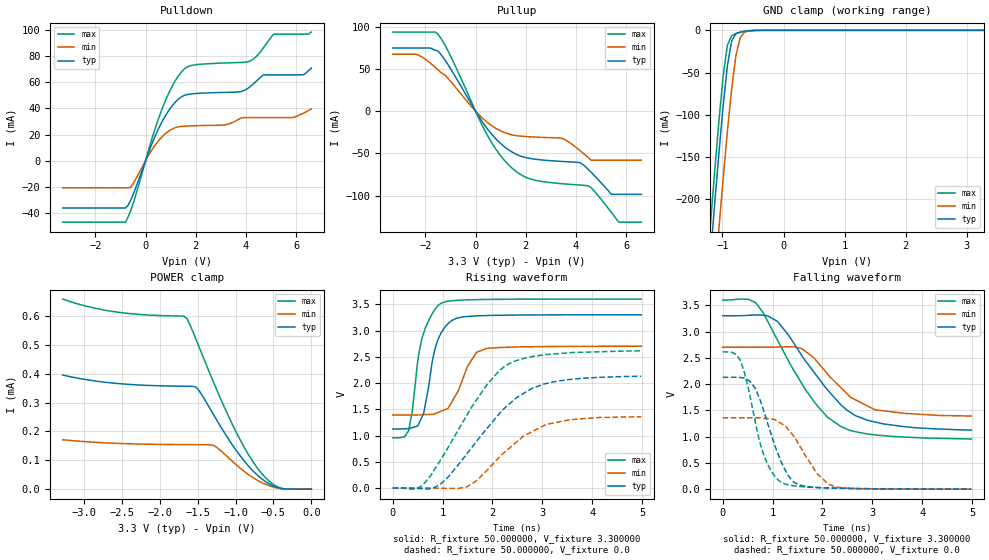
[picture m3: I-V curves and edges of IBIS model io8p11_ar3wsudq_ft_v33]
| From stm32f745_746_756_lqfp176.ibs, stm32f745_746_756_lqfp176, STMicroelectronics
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|   Model io8p11_ar3wsudq_ft_v33
[Model]  io8p11_ar3wsudq_ft_v33
Model_type I/O
Polarity   Non-Inverting
Enable   Active-Low
Vinl =   0.990000V
Vinh =   2.310000V
Vmeas =  1.650000V
Cref =   30.000000pF
Rref =   100.000000M
Vref =   0.0V
C_comp   3.857500pF   3.760500pF   3.941700pF
[Temperature Range]   25.000000   0.125000k   -40.000000
[Pullup Reference]   3.300000V   2.700000V   3.600000V
[Pulldown Reference]   0.0V   0.0V   0.0V
[POWER Clamp Reference]   3.300000V   2.700000V   3.600000V
[GND Clamp Reference]   0.0V   0.0V   0.0V
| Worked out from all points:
|   slope of the pulldown table from 0 to 0.495 V, typ, clamps not added: 20.9 ohm
|   slope of the pullup table from 0 to 0.495 V, typ, clamps not added: 22.6 ohm
|   GND clamp passes 1 mA (typ) near -0.62 V on its own axis
|   rising waveform, R_fixture 50.000000, V_fixture 3.300000: 20-80 % time 277ps typ, 389ps min, 271ps max; typ from 1.12 V to 3.3 V
|   rising waveform, R_fixture 50.000000, V_fixture 0.0: 20-80 % time 1.16ns typ, 999ps min, 1.05ns max; typ from 0 V to 2.13 V
|   falling waveform, R_fixture 50.000000, V_fixture 3.300000: 20-80 % time 1.06ns typ, 876ps min, 1.03ns max; typ from 3.3 V to 1.12 V
|   falling waveform, R_fixture 50.000000, V_fixture 0.0: 20-80 % time 473ps typ, 561ps min, 410ps max; typ from 2.13 V to 0 V
[Pulldown]
|Voltage   I(typ)   I(min)   I(max)
-3.3V     -36.18mA   -20.77mA   -47.07mA
-800mV    -36.18mA   -20.77mA   -47.07mA
-600mV    -30.5mA    -20.52mA   -38.69mA
700mV     31.4mA     19.11mA    41.71mA
1.2V      45.15mA    25.37mA    61.75mA
1.6V      50.35mA    26.5mA     71.06mA
3.1V      52.28mA    27.26mA    74.76mA
4.1V      55.7mA     32.99mA    75.8mA
4.7V      65.72mA    32.99mA    86.64mA
5.1V      65.72mA    32.99mA    96.89mA
6.3V      65.85mA    36.5mA     96.89mA
6.6V      70.91mA    39.71mA    98.45mA
[Pullup]
|Voltage   I(typ)   I(min)   I(max)
-3.3V     74.74mA    67.41mA    93.6mA
-2.3V     74.74mA    66.57mA    93.6mA
-1.5V     71.35mA    49.01mA    91.01mA
-1V       50.51mA    35.5mA     65.49mA
500mV     -22.07mA   -14mA      -30.03mA
1.6V      -50.64mA   -28.81mA   -70.96mA
3.5V      -59.53mA   -32.72mA   -85.92mA
4.2V      -61.52mA   -47.6mA    -87.46mA
4.5V      -69.21mA   -55.15mA   -88.43mA
5.4V      -98.3mA    -57.9mA    -119.4mA
5.7V      -98.3mA    -57.9mA    -131.3mA
6.6V      -98.3mA    -57.9mA    -131.3mA
[GND_clamp]
|Voltage   I(typ)   I(min)   I(max)
-3.3V     -2.332A    -2.407A    -2.312A
-1.2V     -270.2mA   -361.4mA   -232.1mA
-1.13V    -207.3mA   -298.1mA   -169mA
-1.06V    -146.7mA   -236.2mA   -108.8mA
-990mV    -90.18mA   -176.4mA   -54.96mA
-920mV    -42.21mA   -120mA     -17.68mA
-850mV    -12.57mA   -69.47mA   -6.265mA
-780mV    -3.971mA   -30.01mA   -3.886mA
-710mV    -2.1mA     -8.615mA   -2.382mA
-640mV    -1.148mA   -2.283mA   -1.22mA
-570mV    -524uA     -821.5uA   -476.8uA
3.28V     0A         0A         0A
[POWER_clamp]
|Voltage   I(typ)   I(min)   I(max)
-3.28V    395.3uA    171.3uA    658.7uA
-2.6V     367.1uA    159uA      614.9uA
-1.68V    356.7uA    154.4uA    599.4uA
-1.64V    356.5uA    154.4uA    590.8uA
-1.52V    353.6uA    154.3uA    518.3uA
-1.48V    341.1uA    154.2uA    492.3uA
-1.28V    253.6uA    150.4uA    364.2uA
-960mV    123.1uA    77.55uA    181.6uA
-720mV    50.52uA    32.03uA    76.18uA
-560mV    18.94uA    12.27uA    28.65uA
-440mV    5.104uA    3.69uA     7.327uA
0V        0A         0A         0A
[Ramp]
| variable   typ   min   max
dV/dt_r  1.26480/1.15826n   0.80718/0.99319n   1.56168/1.04884n
dV/dt_f  1.28058/1.04420n   0.77238/0.86423n   1.57183/1.02291n
R_load = 50.000000
[Rising Waveform]
R_fixture= 50.000000
V_fixture= 3.300000
V_fixture_min= 2.700000
V_fixture_max= 3.600000
|time   V(typ)   V(min)   V(max)
0s        1.124V     1.392V     954.2mV
320.3ps   1.132V     1.392V     1.095V
510.5ps   1.198V     1.392V     2.472V
650.7ps   1.572V     1.398V     3.038V
830.8ps   2.587V     1.409V     3.379V
971ps     2.956V     1.464V     3.518V
1.111ns   3.131V     1.521V     3.558V
1.682ns   3.279V     2.586V     3.588V
1.882ns   3.285V     2.658V     3.592V
4.985ns   3.3V       2.7V       3.599V
[Rising Waveform]
R_fixture= 50.000000
V_fixture= 0.0
V_fixture_min= 0.0
V_fixture_max= 0.0
|time   V(typ)   V(min)   V(max)
0s        211.3uV    82.5uV     620.3uV
550.6ps   -10.61mV   -118.1uV   23.34mV
951ps     68.5mV     -3.812mV   522.2mV
1.491ns   657mV      24.76mV    1.394V
1.882ns   1.125V     327.8mV    1.959V
2.282ns   1.554V     713.3mV    2.341V
2.783ns   1.893V     1.068V     2.502V
3.073ns   1.99V      1.209V     2.542V
3.574ns   2.07V      1.304V     2.578V
4.985ns   2.129V     1.359V     2.612V
[Falling Waveform]
R_fixture= 50.000000
V_fixture= 3.300000
V_fixture_min= 2.700000
V_fixture_max= 3.600000
|time   V(typ)   V(min)   V(max)
0s        3.3V       2.7V       3.599V
660.7ps   3.315V     2.7V       3.55V
810.8ps   3.309V     2.701V     3.362V
1.101ns   3.19V      2.705V     2.832V
1.582ns   2.549V     2.679V     2.015V
2.102ns   1.889V     2.19V      1.369V
2.362ns   1.611V     1.937V     1.198V
2.663ns   1.399V     1.7V       1.094V
3.063ns   1.277V     1.509V     1.032V
4.985ns   1.124V     1.392V     954.2mV
[Falling Waveform]
R_fixture= 50.000000
V_fixture= 0.0
V_fixture_min= 0.0
V_fixture_max= 0.0
|time   V(typ)   V(min)   V(max)
0s        2.129V     1.359V     2.612V
350.4ps   2.124V     1.358V     2.455V
510.5ps   2.073V     1.358V     1.936V
660.7ps   1.908V     1.357V     1.247V
860.9ps   1.374V     1.347V     562.2mV
1.191ns   478.2mV    1.241V     122.4mV
1.491ns   98.53mV    909.4mV    56.42mV
1.902ns   30.97mV    285.2mV    31.51mV
2.282ns   18.26mV    39.55mV    19.07mV
4.985ns   211.3uV    82.5uV     620.3uV
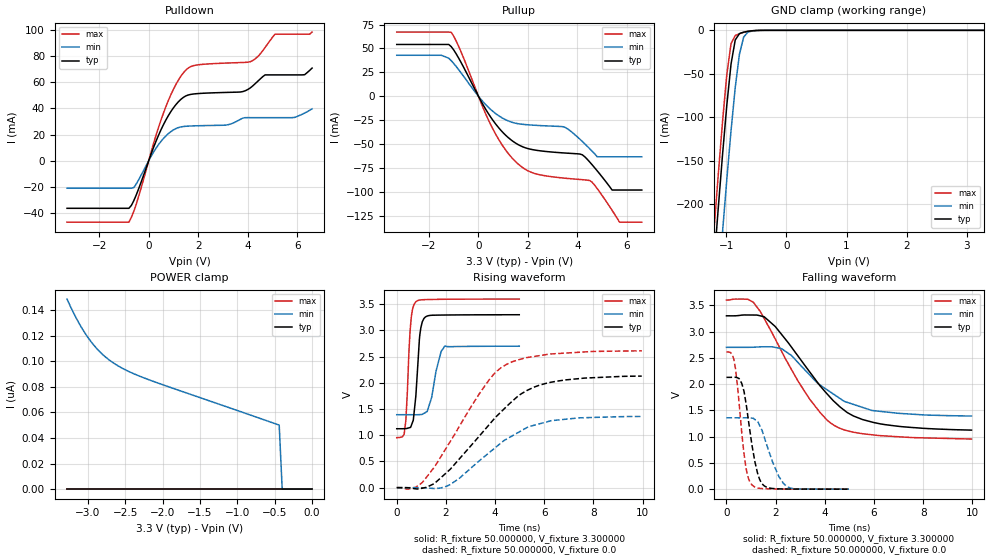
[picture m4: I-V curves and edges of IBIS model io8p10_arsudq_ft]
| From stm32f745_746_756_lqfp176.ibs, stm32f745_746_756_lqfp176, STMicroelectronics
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|   Model io8p10_arsudq_ft
[Model]  io8p10_arsudq_ft
Model_type I/O
Polarity   Non-Inverting
Enable   Active-Low
Vinl =   0.990000V
Vinh =   2.310000V
Vmeas =  1.650000V
Cref =   40.000000pF
Rref =   100.000000M
Vref =   0.0V
C_comp   2.292100pF   2.228000pF   2.366600pF
[Temperature Range]   25.000000   0.125000k   -40.000000
[Pullup Reference]   3.300000V   2.700000V   3.600000V
[Pulldown Reference]   0.0V   0.0V   0.0V
[POWER Clamp Reference]   3.300000V   2.700000V   3.600000V
[GND Clamp Reference]   0.0V   0.0V   0.0V
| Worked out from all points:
|   slope of the pulldown table from 0 to 0.495 V, typ, clamps not added: 20.9 ohm
|   slope of the pullup table from 0 to 0.495 V, typ, clamps not added: 22.6 ohm
|   GND clamp passes 1 mA (typ) near -0.62 V on its own axis
|   rising waveform, R_fixture 50.000000, V_fixture 3.300000: 20-80 % time 194ps typ, 343ps min, 164ps max; typ from 1.12 V to 3.3 V
|   rising waveform, R_fixture 50.000000, V_fixture 0.0: 20-80 % time 2.51ns typ, 2.3ns min, 2.11ns max; typ from 0 V to 2.13 V
|   falling waveform, R_fixture 50.000000, V_fixture 3.300000: 20-80 % time 2.26ns typ, 2.05ns min, 2.03ns max; typ from 3.3 V to 1.12 V
|   falling waveform, R_fixture 50.000000, V_fixture 0.0: 20-80 % time 433ps typ, 634ps min, 341ps max; typ from 2.13 V to 0 V
[Pulldown]
|Voltage   I(typ)   I(min)   I(max)
-3.3V     -36.46mA   -21.09mA   -47.09mA
-800mV    -36.46mA   -21.09mA   -47.09mA
-600mV    -30.5mA    -20.54mA   -38.69mA
700mV     31.4mA     19.11mA    41.71mA
1.2V      45.15mA    25.37mA    61.75mA
1.6V      50.35mA    26.5mA     71.06mA
3.1V      52.28mA    27.26mA    74.76mA
4.1V      55.7mA     33mA       75.81mA
4.7V      65.72mA    33mA       86.7mA
5.1V      65.72mA    33mA       96.91mA
6.3V      65.88mA    36.51mA    96.91mA
6.6V      70.94mA    39.72mA    98.51mA
[Pullup]
|Voltage   I(typ)   I(min)   I(max)
-3.3V     54.23mA    42.91mA    67.18mA
-1.1V     51.99mA    37.29mA    66.9mA
500mV     -22.07mA   -14mA      -30.03mA
1.5V      -49.1mA    -28.3mA    -68.56mA
2.2V      -56.05mA   -30.32mA   -80.35mA
3.5V      -59.53mA   -32.65mA   -85.92mA
4.2V      -61.43mA   -47.49mA   -87.46mA
4.5V      -69.07mA   -55.12mA   -88.38mA
4.8V      -78.23mA   -63.5mA    -96.83mA
5.4V      -98.3mA    -63.5mA    -119.6mA
5.7V      -98.3mA    -63.5mA    -132mA
6.6V      -98.3mA    -63.5mA    -132mA
[GND_clamp]
|Voltage   I(typ)   I(min)   I(max)
-3.3V     -2.318A    -2.397A    -2.291A
-1.2V     -265.5mA   -356.1mA   -227.2mA
-1.13V    -202.6mA   -292.9mA   -164.1mA
-1.06V    -142.2mA   -231.2mA   -104.1mA
-990mV    -85.98mA   -171.6mA   -50.72mA
-920mV    -38.8mA    -115.5mA   -15.28mA
-850mV    -11.08mA   -65.6mA    -6.001mA
-780mV    -3.782mA   -27.42mA   -3.876mA
-710mV    -2.086mA   -7.69mA    -2.381mA
-640mV    -1.147mA   -2.118mA   -1.22mA
-570mV    -523.9uA   -798.4uA   -476.8uA
3.28V     0A         0A         0A
[POWER_clamp]
|Voltage   I(typ)   I(min)   I(max)
-3.28V    0A         148.5nA    0A
-3.2V     0A         138.6nA    0A
-3.12V    0A         129.7nA    0A
-3.04V    0A         122nA      0A
-2.96V    0A         115.3nA    0A
-2.8V     0A         105.1nA    0A
-2.6V     0A         96.44nA    0A
-2.4V     0A         90.52nA    0A
-2.16V    0A         84.97nA    0A
-440mV    0A         50.04nA    0A
-400mV    0A         0A         0A
0V        0A         0A         0A
[Ramp]
| variable   typ   min   max
dV/dt_r  1.26738/2.50869n   0.81168/2.29918n   1.56474/2.11268n
dV/dt_f  1.28316/2.24153n   0.77790/2.04412n   1.57501/2.02550n
R_load = 50.000000
[Rising Waveform]
R_fixture= 50.000000
V_fixture= 3.300000
V_fixture_min= 2.700000
V_fixture_max= 3.600000
|time   V(typ)   V(min)   V(max)
0s        1.124V     1.392V     954.3mV
300.3ps   1.126V     1.392V     1.017V
370.4ps   1.128V     1.392V     1.281V
550.6ps   1.148V     1.392V     3.03V
670.7ps   1.283V     1.391V     3.451V
760.8ps   1.674V     1.391V     3.537V
940.9ps   2.922V     1.394V     3.581V
1.171ns   3.259V     1.435V     3.588V
1.962ns   3.294V     2.703V     3.595V
4.985ns   3.3V       2.7V       3.599V
[Rising Waveform]
R_fixture= 50.000000
V_fixture= 0.0
V_fixture_min= 0.0
V_fixture_max= 0.0
|time   V(typ)   V(min)   V(max)
0s        344.5uV    197.3uV    679.2uV
460.5ps   -2.486mV   133.4uV    -29.06mV
1.041ns   -10.16mV   -1.94mV    97.36mV
1.542ns   82.08mV    -17.48mV   399.3mV
2.142ns   336.2mV    50.19mV    853.9mV
3.744ns   1.194V     660.5mV    2.047V
4.444ns   1.537V     920.1mV    2.347V
5.285ns   1.851V     1.144V     2.482V
6.166ns   2V         1.262V     2.545V
9.97ns    2.129V     1.359V     2.612V
[Falling Waveform]
R_fixture= 50.000000
V_fixture= 3.300000
V_fixture_min= 2.700000
V_fixture_max= 3.600000
|time   V(typ)   V(min)   V(max)
0s        3.3V       2.7V       3.599V
880.9ps   3.316V     2.7V       3.613V
1.101ns   3.315V     2.702V     3.552V
1.542ns   3.279V     2.711V     3.243V
2.242ns   2.946V     2.674V     2.625V
3.383ns   2.234V     2.176V     1.715V
4.404ns   1.659V     1.794V     1.208V
5.165ns   1.394V     1.614V     1.085V
6.206ns   1.248V     1.483V     1.02V
9.97ns    1.124V     1.392V     954.3mV
[Falling Waveform]
R_fixture= 50.000000
V_fixture= 0.0
V_fixture_min= 0.0
V_fixture_max= 0.0
|time   V(typ)   V(min)   V(max)
0s        2.129V     1.359V     2.612V
300.3ps   2.13V      1.359V     2.474V
450.5ps   2.119V     1.358V     1.956V
620.6ps   2.015V     1.358V     1.084V
840.8ps   1.49V      1.36V      297.5mV
1.041ns   831.1mV    1.352V     81.17mV
1.451ns   102.9mV    1.114V     12.05mV
1.882ns   12.93mV    511mV      4.738mV
2.432ns   3.272mV    61.72mV    2.497mV
4.985ns   344.5uV    197.3uV    679.2uV
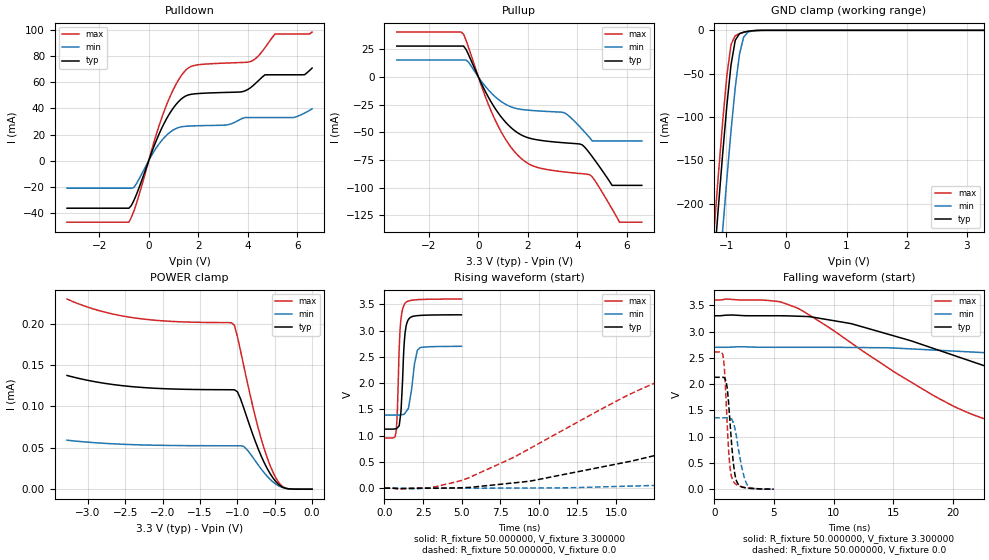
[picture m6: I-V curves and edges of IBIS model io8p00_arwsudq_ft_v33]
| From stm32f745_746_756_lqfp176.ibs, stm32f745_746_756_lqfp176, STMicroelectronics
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|   Model io8p00_arwsudq_ft_v33
[Model]  io8p00_arwsudq_ft_v33
Model_type I/O
Polarity   Non-Inverting
Enable   Active-Low
Vinl =   0.990000V
Vinh =   2.310000V
Vmeas =  1.650000V
Cref =   50.000000pF
Rref =   100.000000M
Vref =   0.0V
C_comp   2.911600pF   2.826500pF   2.975800pF
[Temperature Range]   25.000000   0.125000k   -40.000000
[Pullup Reference]   3.300000V   2.700000V   3.600000V
[Pulldown Reference]   0.0V   0.0V   0.0V
[POWER Clamp Reference]   3.300000V   2.700000V   3.600000V
[GND Clamp Reference]   0.0V   0.0V   0.0V
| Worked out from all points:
|   slope of the pulldown table from 0 to 0.495 V, typ, clamps not added: 20.9 ohm
|   slope of the pullup table from 0 to 0.495 V, typ, clamps not added: 22.6 ohm
|   GND clamp passes 1 mA (typ) near -0.62 V on its own axis
|   rising waveform, R_fixture 50.000000, V_fixture 3.300000: 20-80 % time 220ps typ, 367ps min, 188ps max; typ from 1.12 V to 3.3 V
|   rising waveform, R_fixture 50.000000, V_fixture 0.0: 20-80 % time 19.7ns typ, 51.6ns min, 10.4ns max; typ from 0 V to 2.13 V
|   falling waveform, R_fixture 50.000000, V_fixture 3.300000: 20-80 % time 18.7ns typ, 38.3ns min, 11.3ns max; typ from 3.3 V to 1.12 V
|   falling waveform, R_fixture 50.000000, V_fixture 0.0: 20-80 % time 462ps typ, 672ps min, 374ps max; typ from 2.13 V to 0 V
[Pulldown]
|Voltage   I(typ)   I(min)   I(max)
-3.3V     -36.38mA   -21.07mA   -47.08mA
-800mV    -36.38mA   -21.07mA   -47.08mA
-600mV    -30.5mA    -20.54mA   -38.69mA
700mV     31.4mA     19.11mA    41.71mA
1.2V      45.15mA    25.37mA    61.75mA
1.6V      50.35mA    26.5mA     71.06mA
3.1V      52.28mA    27.26mA    74.76mA
4.1V      55.71mA    33.02mA    75.8mA
4.7V      65.8mA     33.02mA    86.64mA
5.1V      65.8mA     33.02mA    97.03mA
6.3V      65.87mA    36.5mA     97.03mA
6.6V      70.93mA    39.72mA    98.49mA
[Pullup]
|Voltage   I(typ)   I(min)   I(max)
-3.3V     28.03mA    15.43mA    40.67mA
-700mV    28.03mA    15.43mA    40.67mA
-400mV    20.31mA    13.47mA    26.93mA
600mV     -25.77mA   -16.23mA   -35.14mA
1.6V      -50.64mA   -28.81mA   -70.96mA
2.3V      -56.49mA   -30.48mA   -81.16mA
3.5V      -59.53mA   -32.66mA   -85.92mA
4.2V      -61.45mA   -47.47mA   -87.46mA
4.5V      -69.1mA    -55.01mA   -88.4mA
5.4V      -98mA      -57.8mA    -119.3mA
5.7V      -98mA      -57.8mA    -131.3mA
6.6V      -98mA      -57.8mA    -131.3mA
[GND_clamp]
|Voltage   I(typ)   I(min)   I(max)
-3.3V     -2.321A    -2.397A    -2.298A
-1.2V     -266.4mA   -356.3mA   -229.4mA
-1.13V    -203.6mA   -293.1mA   -166.3mA
-1.06V    -143.2mA   -231.4mA   -106.2mA
-990mV    -86.95mA   -171.8mA   -52.65mA
-920mV    -39.66mA   -115.8mA   -16.36mA
-850mV    -11.49mA   -65.84mA   -6.11mA
-780mV    -3.834mA   -27.59mA   -3.88mA
-710mV    -2.09mA    -7.753mA   -2.381mA
-640mV    -1.147mA   -2.129mA   -1.22mA
-570mV    -523.9uA   -800uA     -476.8uA
3.28V     0A         0A         0A
[POWER_clamp]
|Voltage   I(typ)   I(min)   I(max)
-3.28V    137.3uA    59.14uA    229.6uA
-2.36V    123.4uA    53.65uA    206.6uA
-1.08V    120.1uA    52.41uA    201.1uA
-1.04V    120uA      52.41uA    198uA
-1V       117.7uA    52.4uA     184.5uA
-920mV    99.46uA    51.91uA    151.2uA
-720mV    48.42uA    29.12uA    73.51uA
-600mV    24.82uA    15.47uA    37.72uA
-520mV    13.1uA     8.45uA     19.84uA
-440mV    5.058uA    3.61uA     7.276uA
-360mV    1.193uA    1.129uA    1.311uA
0V        0A         0A         0A
[Ramp]
| variable   typ   min   max
dV/dt_r  1.27758/19.64364n   0.81588/51.74005n   1.56732/10.36922n
dV/dt_f  1.30572/18.71858n   0.78498/38.44047n   1.58792/11.30041n
R_load = 50.000000
[Rising Waveform]
R_fixture= 50.000000
V_fixture= 3.300000
V_fixture_min= 2.700000
V_fixture_max= 3.600000
|time   V(typ)   V(min)   V(max)
0s        1.124V     1.392V     953.5mV
760.8ps   1.132V     1.392V     1.092V
840.8ps   1.153V     1.391V     1.531V
951ps     1.188V     1.391V     2.644V
1.011ns   1.325V     1.394V     3.024V
1.071ns   1.469V     1.396V     3.224V
1.301ns   2.847V     1.418V     3.504V
1.552ns   3.212V     1.521V     3.563V
2.132ns   3.284V     2.626V     3.589V
4.985ns   3.3V       2.7V       3.6V
[Rising Waveform]
R_fixture= 50.000000
V_fixture= 0.0
V_fixture_min= 0.0
V_fixture_max= 0.0
|time   V(typ)   V(min)   V(max)
0s        121.1nV    275.7nV    640.8nV
5.005ns   7.053mV    -124uV     146.9mV
9.51ns    138.3mV    3.284mV    770.8mV
16.02ns   516.5mV    39.8mV     1.805V
19.52ns   762.2mV    67.82mV    2.203V
26.03ns   1.208V     156.9mV    2.466V
34.03ns   1.699V     288.4mV    2.558V
55.56ns   2.06V      687.6mV    2.606V
108.6ns   2.126V     1.269V     2.612V
249.2ns   2.129V     1.359V     2.612V
[Falling Waveform]
R_fixture= 50.000000
V_fixture= 3.300000
V_fixture_min= 2.700000
V_fixture_max= 3.600000
|time   V(typ)   V(min)   V(max)
0s        3.3V       2.7V       3.6V
7.007ns   3.292V     2.7V       3.443V
11.51ns   3.148V     2.697V     2.777V
18.52ns   2.666V     2.646V     1.763V
22.52ns   2.357V     2.599V     1.348V
32.53ns   1.662V     2.394V     1.061V
47.05ns   1.268V     2.064V     995.1mV
63.06ns   1.184V     1.719V     967.9mV
84.58ns   1.147V     1.536V     956.9mV
249.2ns   1.124V     1.392V     953.5mV
[Falling Waveform]
R_fixture= 50.000000
V_fixture= 0.0
V_fixture_min= 0.0
V_fixture_max= 0.0
|time   V(typ)   V(min)   V(max)
0s        2.129V     1.359V     2.612V
640.6ps   2.129V     1.359V     2.602V
790.8ps   2.125V     1.358V     2.465V
1.001ns   2.047V     1.358V     1.676V
1.221ns   1.594V     1.356V     696.1mV
1.361ns   1.158V     1.345V     351.9mV
1.552ns   626.6mV    1.29V      177mV
1.902ns   138.1mV    945.5mV    81.88mV
2.713ns   22.69mV    103mV      29.55mV
4.985ns   121.1nV    275.7nV    640.8nV
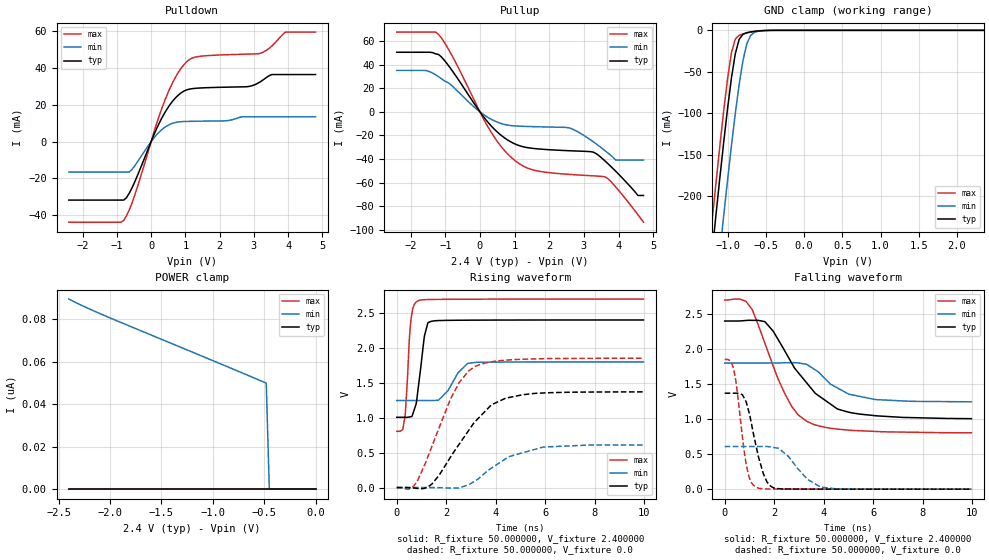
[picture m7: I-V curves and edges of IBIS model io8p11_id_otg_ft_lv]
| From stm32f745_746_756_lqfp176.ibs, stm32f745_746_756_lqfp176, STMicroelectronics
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|   Model io8p11_id_otg_ft_lv
[Model]  io8p11_id_otg_ft_lv
Model_type I/O
Polarity   Non-Inverting
Enable   Active-Low
Vinl =   0.720000V
Vinh =   1.680000V
Vmeas =  1.200000V
Cref =   30.000000pF
Rref =   100.000000M
Vref =   0.0V
C_comp   2.229800pF   2.169700pF   2.325100pF
[Temperature Range]   25.000000   0.125000k   -40.000000
[Pullup Reference]   2.400000V   1.800000V   2.700000V
[Pulldown Reference]   0.0V   0.0V   0.0V
[POWER Clamp Reference]   2.400000V   1.800000V   2.700000V
[GND Clamp Reference]   0.0V   0.0V   0.0V
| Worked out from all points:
|   slope of the pulldown table from 0 to 0.36 V, typ, clamps not added: 25 ohm
|   slope of the pullup table from 0 to 0.36 V, typ, clamps not added: 27.7 ohm
|   GND clamp passes 1 mA (typ) near -0.62 V on its own axis
|   rising waveform, R_fixture 50.000000, V_fixture 2.400000: 20-80 % time 281ps typ, 624ps min, 184ps max; typ from 1.01 V to 2.4 V
|   rising waveform, R_fixture 50.000000, V_fixture 0.0: 20-80 % time 1.7ns typ, 1.69ns min, 1.31ns max; typ from 0 V to 1.37 V
|   falling waveform, R_fixture 50.000000, V_fixture 2.400000: 20-80 % time 1.81ns typ, 1.29ns min, 1.32ns max; typ from 2.4 V to 1.01 V
|   falling waveform, R_fixture 50.000000, V_fixture 0.0: 20-80 % time 535ps typ, 926ps min, 384ps max; typ from 1.37 V to 0 V
[Pulldown]
|Voltage   I(typ)   I(min)   I(max)
-2.4V     -31.73mA   -16.51mA   -43.74mA
-800mV    -31.73mA   -16.51mA   -42.87mA
-480mV    -21.98mA   -13.17mA   -29.21mA
80mV      3.63mA     1.966mA    5.014mA
480mV     18.16mA    8.738mA    26.02mA
800mV     25.38mA    10.72mA    37.77mA
1.12V     28.53mA    11.02mA    44.6mA
2.8V      29.84mA    13.49mA    47.53mA
3.2V      32.65mA    13.49mA    48.05mA
3.52V     36.43mA    13.49mA    51.84mA
3.92V     36.43mA    13.49mA    59.49mA
4.8V      36.43mA    13.49mA    59.49mA
[Pullup]
|Voltage   I(typ)   I(min)   I(max)
-2.4V     50.45mA    35.08mA    67.53mA
-1.52V    50.45mA    34.74mA    67.53mA
-1.2V     48.64mA    29.87mA    65.68mA
320mV     -11.75mA   -6.207mA   -17.08mA
1.04V     -27.54mA   -11.97mA   -41.91mA
1.6V      -31.14mA   -12.58mA   -49.63mA
2.56V     -32.88mA   -13.48mA   -52.9mA
3.28V     -34.19mA   -25.52mA   -54.18mA
3.6V      -41.31mA   -32.62mA   -54.97mA
3.92V     -50.32mA   -40.8mA    -63.63mA
4.56V     -70.8mA    -40.8mA    -87.08mA
4.72V     -70.8mA    -40.8mA    -93.4mA
[GND_clamp]
|Voltage   I(typ)   I(min)   I(max)
-2.4V     -1.424A    -1.508A    -1.393A
-1.25V    -311.2mA   -401.9mA   -273.3mA
-1.2V     -265.4mA   -356.1mA   -227.2mA
-1.15V    -220.4mA   -310.8mA   -181.9mA
-1.1V     -176.3mA   -266.2mA   -137.9mA
-1.05V    -133.8mA   -222.5mA   -95.88mA
-950mV    -57.31mA   -138.9mA   -26.99mA
-900mV    -28.28mA   -100.4mA   -10.61mA
-850mV    -11.02mA   -65.55mA   -5.978mA
-750mV    -2.847mA   -16.51mA   -3.192mA
-600mV    -755.4uA   -1.17mA    -743.6uA
2.35V     0A         0A         0A
[POWER_clamp]
|Voltage   I(typ)   I(min)   I(max)
-2.4V     0A         89.62nA    0A
-2.04V    0A         81.58nA    0A
-480mV    0A         50.01nA    0A
-450mV    0A         0A         0A
0V        0A         0A         0A
[Ramp]
| variable   typ   min   max
dV/dt_r  0.82182/1.69452n   0.36406/1.67984n   1.11108/1.30721n
dV/dt_f  0.83262/1.80351n   0.33288/1.29652n   1.13587/1.32318n
R_load = 50.000000
[Rising Waveform]
R_fixture= 50.000000
V_fixture= 2.400000
V_fixture_min= 1.800000
V_fixture_max= 2.700000
|time   V(typ)   V(min)   V(max)
0s        1.006V     1.247V     804.6mV
240.2ps   1.006V     1.247V     832mV
340.3ps   1.006V     1.247V     1.037V
500.5ps   1.01V      1.247V     2.078V
580.6ps   1.015V     1.247V     2.425V
840.8ps   1.352V     1.247V     2.671V
1.121ns   2.175V     1.247V     2.691V
1.381ns   2.379V     1.245V     2.694V
2.883ns   2.397V     1.779V     2.697V
9.97ns    2.4V       1.8V       2.699V
[Rising Waveform]
R_fixture= 50.000000
V_fixture= 0.0
V_fixture_min= 0.0
V_fixture_max= 0.0
|time   V(typ)   V(min)   V(max)
0s        169.6uV    66.22uV    557.4uV
680.7ps   -5.465mV   52.05uV    19.58mV
1.421ns   50.6mV     101.3uV    591.9mV
2.162ns   430.7mV    -7.087mV   1.26V
2.523ns   621.8mV    -3.249mV   1.504V
3.143ns   936.1mV    90.65mV    1.73V
3.824ns   1.185V     278mV      1.801V
4.384ns   1.277V     409.1mV    1.823V
5.926ns   1.355V     580.5mV    1.846V
9.97ns    1.37V      609mV      1.852V
[Falling Waveform]
R_fixture= 50.000000
V_fixture= 2.400000
V_fixture_min= 1.800000
V_fixture_max= 2.700000
|time   V(typ)   V(min)   V(max)
0s        2.4V       1.8V       2.699V
840.8ps   2.407V     1.8V       2.685V
1.101ns   2.41V      1.8V       2.569V
1.622ns   2.391V     1.8V       2.085V
2.422ns   1.977V     1.804V     1.369V
2.963ns   1.668V     1.802V     1.064V
3.323ns   1.513V     1.78V      968.1mV
4.545ns   1.147V     1.446V     857.9mV
5.025ns   1.098V     1.355V     842.9mV
9.97ns    1.006V     1.247V     804.6mV
[Falling Waveform]
R_fixture= 50.000000
V_fixture= 0.0
V_fixture_min= 0.0
V_fixture_max= 0.0
|time   V(typ)   V(min)   V(max)
0s        1.37V      609mV      1.852V
360.4ps   1.37V      609mV      1.719V
460.5ps   1.37V      609mV      1.524V
720.7ps   1.345V     608.9mV    731mV
961ps     1.125V     608.7mV    202.3mV
1.281ns   595.1mV    608.7mV    26.74mV
1.702ns   108.3mV    609.8mV    3.308mV
2.062ns   12.58mV    589.9mV    2.065mV
3.884ns   927.5uV    29.67mV    1.076mV
9.97ns    169.6uV    66.22uV    557.4uV
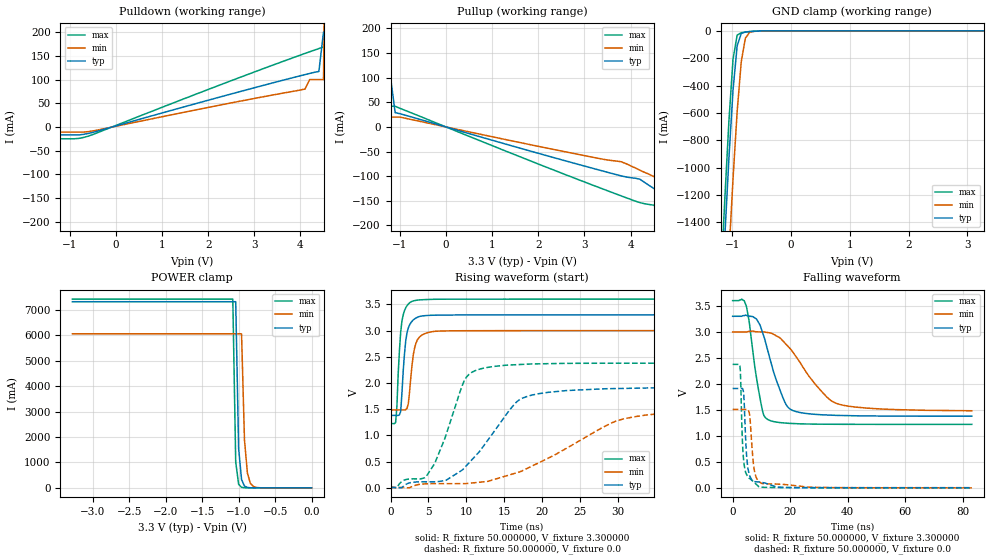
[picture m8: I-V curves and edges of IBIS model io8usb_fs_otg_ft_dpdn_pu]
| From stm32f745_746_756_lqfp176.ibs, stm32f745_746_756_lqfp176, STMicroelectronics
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|   Model io8usb_fs_otg_ft_dpdn_pu
[Model]  io8usb_fs_otg_ft_dpdn_pu
Model_type I/O
Polarity   Non-Inverting
Enable   Active-Low
Vinl =   0.990000V
Vinh =   2.310000V
Vmeas =  1.650000V
Cref =   50.000000pF
Rref =   100.000000M
Vref =   0.0V
C_comp   8.255900pF   7.991100pF   8.650600pF
[Temperature Range]   25.000000   0.125000k   -40.000000
[Pullup Reference]   3.300000V   3.000000V   3.600000V
[Pulldown Reference]   0.0V   0.0V   0.0V
[POWER Clamp Reference]   3.300000V   3.000000V   3.600000V
[GND Clamp Reference]   0.0V   0.0V   0.0V
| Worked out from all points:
|   slope of the pulldown table from 0 to 0.495 V, typ, clamps not added: 36.5 ohm
|   slope of the pullup table from 0 to 0.495 V, typ, clamps not added: 36.9 ohm
|   GND clamp passes 1 mA (typ) near -0.52 V on its own axis
|   POWER clamp passes 1 mA (typ) near -0.77 V on its own axis
|   rising waveform, R_fixture 50.000000, V_fixture 3.300000: 20-80 % time 644ps typ, 751ps min, 580ps max; typ from 1.38 V to 3.3 V
|   rising waveform, R_fixture 50.000000, V_fixture 0.0: 20-80 % time 6.19ns typ, 11.7ns min, 3.46ns max; typ from 0.008 V to 1.91 V
|   falling waveform, R_fixture 50.000000, V_fixture 3.300000: 20-80 % time 6.44ns typ, 12.4ns min, 3.69ns max; typ from 3.3 V to 1.38 V
|   falling waveform, R_fixture 50.000000, V_fixture 0.0: 20-80 % time 1.21ns typ, 1.46ns min, 1.05ns max; typ from 1.91 V to 0.008 V
[Pulldown]
|Voltage   I(typ)   I(min)   I(max)
-3.3V     -181mA     -10.92mA   -218mA
-3.2V     -136mA     -10.92mA   -212mA
-2.9V     -122mA     -10.92mA   -197mA
-2.8V     -16.88mA   -10.92mA   -24.99mA
-700mV    -15.64mA   -10.92mA   -22.23mA
4.1V      110.4mA    80mA       155.2mA
4.2V      112.9mA    100mA      158.6mA
4.4V      117mA      100mA      165.4mA
4.5V      200mA      100mA      168.8mA
4.6V      200mA      1A         172.1mA
4.8V      1A         1A         200mA
6.6V      1A         1A         1A
[Pullup]
|Voltage   I(typ)   I(min)   I(max)
-3.3V     1A         1A         1A
-1.9V     1A         1A         1A
-1.8V     100mA      1A         1A
-1.7V     100mA      1A         100mA
-1.6V     100mA      1A         100mA
-1.5V     100mA      20mA       100mA
-1.3V     100mA      20mA       100mA
-1.2V     100mA      20mA       42mA
-1.1V     29mA       20mA       42mA
4.2V      -106mA     -87.7mA    -153.5mA
5V        -154.3mA   -123mA     -199.9mA
6.6V      -220mA     -159mA     -317mA
[GND_clamp]
|Voltage   I(typ)   I(min)   I(max)
-3.3V     -9.433A    -9.435A    -9.911A
-1.2V     -2.116A    -2.846A    -1.847A
-1.13V    -1.505A    -2.23A     -1.23A
-1.06V    -930.4mA   -1.637A    -658.9mA
-990mV    -432.7mA   -1.08A     -207.3mA
-920mV    -110.5mA   -590.3mA   -31.59mA
-850mV    -19.84mA   -226.8mA   -13.66mA
-780mV    -8.32mA    -54.05mA   -9.516mA
-710mV    -5.29mA    -11.97mA   -6.271mA
-640mV    -3.236mA   -4.296mA   -3.584mA
3.28V     0A         0A         0A
[POWER_clamp]
|Voltage   I(typ)   I(min)   I(max)
-3.28V    7.329A     6.065A     7.432A
-1.08V    7.329A     6.065A     7.432A
-1.04V    7.329A     6.065A     1.016A
-1V       1.546A     6.065A     140mA
-960mV    326.6mA    6.065A     20.26mA
-920mV    69.53mA    1.891A     3.845mA
-880mV    15.31mA    589.6mA    1.536mA
-840mV    3.837mA    184.1mA    1.157mA
-800mV    1.378mA    57.75mA    1.042mA
-720mV    664.9uA    6.031mA    894.5uA
0V        184nA      121.7nA    386.5nA
[Ramp]
| variable   typ   min   max
dV/dt_r  1.14368/6.18089n   0.90337/11.66724n   1.42004/3.45480n
dV/dt_f  1.15026/6.43166n   0.90582/12.40502n   1.42410/3.68417n
R_load = 50.000000
[Rising Waveform]
R_fixture= 50.000000
V_fixture= 3.300000
V_fixture_min= 3.000000
V_fixture_max= 3.600000
|time   V(typ)   V(min)   V(max)
0s        1.383V     1.487V     1.226V
667.3ps   1.383V     1.487V     1.248V
1.335ns   1.457V     1.487V     2.972V
1.502ns   1.813V     1.487V     3.184V
1.835ns   2.555V     1.487V     3.379V
2.169ns   2.958V     1.517V     3.475V
3.003ns   3.204V     2.542V     3.565V
3.337ns   3.239V     2.754V     3.576V
7.341ns   3.296V     2.994V     3.598V
83.08ns   3.3V       3V         3.6V
[Rising Waveform]
R_fixture= 50.000000
V_fixture= 0.0
V_fixture_min= 0.0
V_fixture_max= 0.0
|time   V(typ)   V(min)   V(max)
0s        8.179mV    7.091mV    10.72mV
4.671ns   116.2mV    77.59mV    212.1mV
7.174ns   139.1mV    80.84mV    947.7mV
9.843ns   399.2mV    81.8mV     2.077V
12.68ns   880.8mV    121.7mV    2.295V
16.35ns   1.598V     276.2mV    2.348V
17.85ns   1.736V     360.2mV    2.358V
29.03ns   1.892V     1.23V      2.377V
33.7ns    1.905V     1.389V     2.377V
83.08ns   1.914V     1.513V     2.377V
[Falling Waveform]
R_fixture= 50.000000
V_fixture= 3.300000
V_fixture_min= 3.000000
V_fixture_max= 3.600000
|time   V(typ)   V(min)   V(max)
0s        3.3V       3V         3.6V
4.671ns   3.32V      3V         3.508V
9.843ns   3.079V     3V         1.629V
10.84ns   2.913V     2.999V     1.4V
12.35ns   2.611V     2.987V     1.314V
17.85ns   1.687V     2.804V     1.253V
21.86ns   1.474V     2.539V     1.24V
29.36ns   1.415V     1.954V     1.23V
36.37ns   1.398V     1.622V     1.227V
83.08ns   1.383V     1.487V     1.226V
[Falling Waveform]
R_fixture= 50.000000
V_fixture= 0.0
V_fixture_min= 0.0
V_fixture_max= 0.0
|time   V(typ)   V(min)   V(max)
0s        1.914V     1.513V     2.377V
2.503ns   1.914V     1.512V     2.35V
3.504ns   1.907V     1.513V     772.5mV
4.004ns   1.664V     1.513V     448.1mV
4.505ns   964.7mV    1.513V     303.8mV
5.005ns   520.8mV    1.514V     246.8mV
5.839ns   249.6mV    1.428V     188.1mV
7.341ns   137.7mV    411.2mV    118.8mV
9.176ns   120.1mV    122.9mV    26.59mV
83.08ns   8.179mV    7.091mV    10.72mV
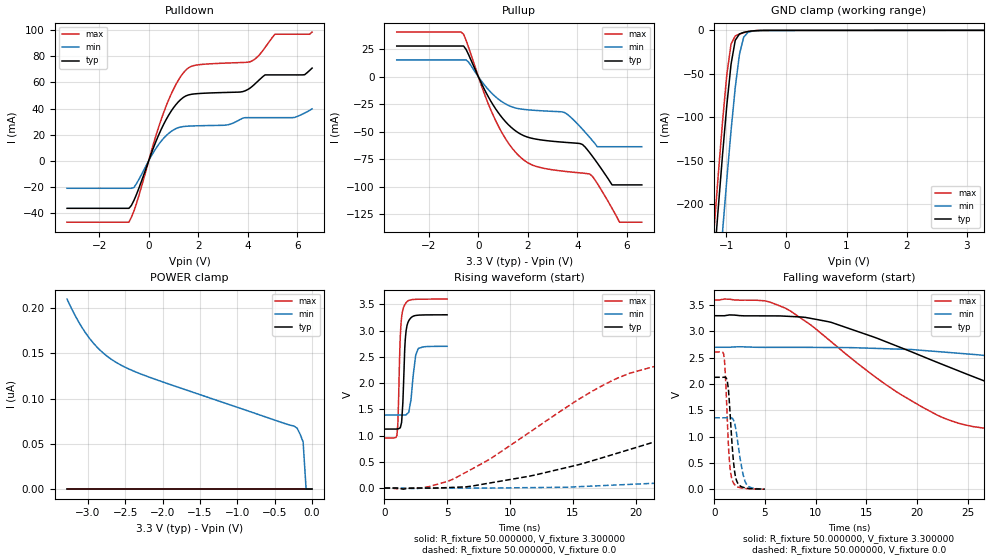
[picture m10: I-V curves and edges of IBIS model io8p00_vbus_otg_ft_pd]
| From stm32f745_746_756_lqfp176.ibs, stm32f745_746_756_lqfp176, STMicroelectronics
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|   Model io8p00_vbus_otg_ft_pd
[Model]  io8p00_vbus_otg_ft_pd
Model_type I/O
Polarity   Non-Inverting
Enable   Active-Low
Vinl =   0.990000V
Vinh =   2.310000V
Vmeas =  1.650000V
Cref =   50.000000pF
Rref =   100.000000M
Vref =   0.0V
C_comp   3.304800pF   3.199300pF   3.429300pF
[Temperature Range]   25.000000   0.125000k   -40.000000
[Pullup Reference]   3.300000V   2.700000V   3.600000V
[Pulldown Reference]   0.0V   0.0V   0.0V
[POWER Clamp Reference]   3.300000V   2.700000V   3.600000V
[GND Clamp Reference]   0.0V   0.0V   0.0V
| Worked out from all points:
|   slope of the pulldown table from 0 to 0.495 V, typ, clamps not added: 20.9 ohm
|   slope of the pullup table from 0 to 0.495 V, typ, clamps not added: 22.6 ohm
|   GND clamp passes 1 mA (typ) near -0.61 V on its own axis
|   rising waveform, R_fixture 50.000000, V_fixture 3.300000: 20-80 % time 223ps typ, 350ps min, 205ps max; typ from 1.12 V to 3.3 V
|   rising waveform, R_fixture 50.000000, V_fixture 0.0: 20-80 % time 19.3ns typ, 47.3ns min, 10.3ns max; typ from 0 V to 2.13 V
|   falling waveform, R_fixture 50.000000, V_fixture 3.300000: 20-80 % time 18.4ns typ, 37.5ns min, 11.4ns max; typ from 3.3 V to 1.12 V
|   falling waveform, R_fixture 50.000000, V_fixture 0.0: 20-80 % time 480ps typ, 675ps min, 387ps max; typ from 2.13 V to 0 V
[Pulldown]
|Voltage   I(typ)   I(min)   I(max)
-3.3V     -36.41mA   -21.08mA   -47.03mA
-800mV    -36.41mA   -21.08mA   -47.03mA
-600mV    -30.48mA   -20.53mA   -38.65mA
700mV     31.4mA     19.11mA    41.71mA
1.2V      45.15mA    25.37mA    61.75mA
1.6V      50.35mA    26.5mA     71.06mA
3.1V      52.27mA    27.26mA    74.75mA
4.1V      55.7mA     32.99mA    75.8mA
4.7V      65.72mA    32.99mA    86.69mA
5.1V      65.72mA    32.99mA    96.9mA
6.3V      65.87mA    36.5mA     96.9mA
6.6V      70.93mA    39.71mA    98.5mA
[Pullup]
|Voltage   I(typ)   I(min)   I(max)
-3.3V     28.03mA    15.43mA    40.69mA
-700mV    28.03mA    15.43mA    40.69mA
-400mV    20.31mA    13.47mA    26.93mA
600mV     -25.77mA   -16.23mA   -35.13mA
1.6V      -50.64mA   -28.81mA   -70.96mA
3.5V      -59.53mA   -32.66mA   -85.92mA
4.2V      -61.44mA   -47.49mA   -87.46mA
4.5V      -69.06mA   -55.13mA   -88.4mA
4.8V      -78.23mA   -63.5mA    -96.84mA
5.4V      -98.2mA    -63.5mA    -119.6mA
5.7V      -98.2mA    -63.5mA    -132.1mA
6.6V      -98.2mA    -63.5mA    -132.1mA
[GND_clamp]
|Voltage   I(typ)   I(min)   I(max)
-3.3V     -2.321A    -2.399A    -2.294A
-1.2V     -265.6mA   -356.2mA   -227.3mA
-1.13V    -202.8mA   -293mA     -164.3mA
-1.06V    -142.3mA   -231.2mA   -104.3mA
-990mV    -86.15mA   -171.7mA   -51.01mA
-920mV    -39.05mA   -115.6mA   -15.73mA
-850mV    -11.41mA   -65.74mA   -6.38mA
-780mV    -4.058mA   -27.6mA    -4.167mA
-710mV    -2.296mA   -7.89mA    -2.605mA
-640mV    -1.302mA   -2.283mA   -1.381mA
-570mV    -629.1uA   -918.9uA   -580.8uA
3.28V     81.28uA    57.87uA    93.98uA
[POWER_clamp]
|Voltage   I(typ)   I(min)   I(max)
-3.28V    0A         210.1nA    0A
-3.12V    0A         184.2nA    0A
-2.96V    0A         164.6nA    0A
-2.8V     0A         150.7nA    0A
-2.6V     0A         139nA      0A
-2.16V    0A         123.2nA    0A
-240mV    0A         69.7nA     0A
-200mV    0A         67.32nA    0A
-160mV    0A         60.72nA    0A
-120mV    0A         52.23nA    0A
-80mV     0A         0A         0A
0V        0A         0A         0A
[Ramp]
| variable   typ   min   max
dV/dt_r  1.27644/19.23909n   0.81486/47.33205n   1.56654/10.30931n
dV/dt_f  1.30536/18.37874n   0.78480/37.61398n   1.58742/11.38956n
R_load = 50.000000
[Rising Waveform]
R_fixture= 50.000000
V_fixture= 3.300000
V_fixture_min= 2.700000
V_fixture_max= 3.600000
|time   V(typ)   V(min)   V(max)
0s        1.123V     1.39V      953.1mV
991ps     1.125V     1.391V     1.003V
1.061ns   1.127V     1.391V     1.214V
1.281ns   1.17V      1.391V     2.993V
1.461ns   1.622V     1.39V      3.392V
1.552ns   2.216V     1.391V     3.458V
1.722ns   2.995V     1.395V     3.53V
2.032ns   3.222V     1.578V     3.58V
2.683ns   3.292V     2.656V     3.596V
4.985ns   3.299V     2.699V     3.599V
[Rising Waveform]
R_fixture= 50.000000
V_fixture= 0.0
V_fixture_min= 0.0
V_fixture_max= 0.0
|time   V(typ)   V(min)   V(max)
0s        7.157nV    351.8nV    4.703nV
5.506ns   13.44mV    -162.8uV   174mV
12.01ns   249.8mV    9.333mV    1.137V
19.52ns   734.8mV    69.79mV    2.186V
25.03ns   1.127V     128.9mV    2.436V
33.03ns   1.633V     243.1mV    2.549V
48.55ns   2.011V     544.9mV    2.601V
87.09ns   2.12V      1.139V     2.611V
157.7ns   2.128V     1.346V     2.611V
249.2ns   2.128V     1.358V     2.611V
[Falling Waveform]
R_fixture= 50.000000
V_fixture= 3.300000
V_fixture_min= 2.700000
V_fixture_max= 3.600000
|time   V(typ)   V(min)   V(max)
0s        3.299V     2.699V     3.599V
5.506ns   3.295V     2.697V     3.558V
11.51ns   3.174V     2.694V     2.808V
17.02ns   2.798V     2.671V     1.978V
22.52ns   2.371V     2.609V     1.363V
31.53ns   1.721V     2.429V     1.074V
46.55ns   1.274V     2.082V     997.5mV
64.06ns   1.181V     1.707V     968.4mV
85.09ns   1.146V     1.532V     956.3mV
249.2ns   1.123V     1.39V      953.1mV
[Falling Waveform]
R_fixture= 50.000000
V_fixture= 0.0
V_fixture_min= 0.0
V_fixture_max= 0.0
|time   V(typ)   V(min)   V(max)
0s        2.128V     1.358V     2.611V
981ps     2.129V     1.357V     2.51V
1.151ns   2.119V     1.357V     1.98V
1.311ns   2.031V     1.357V     1.243V
1.491ns   1.668V     1.359V     562.5mV
1.812ns   732.4mV    1.344V     156.8mV
2.182ns   176.9mV    1.086V     58.14mV
2.573ns   60.68mV    562.4mV    27.39mV
3.033ns   24.88mV    154.5mV    13.11mV
4.985ns   7.157nV    351.8nV    4.703nV
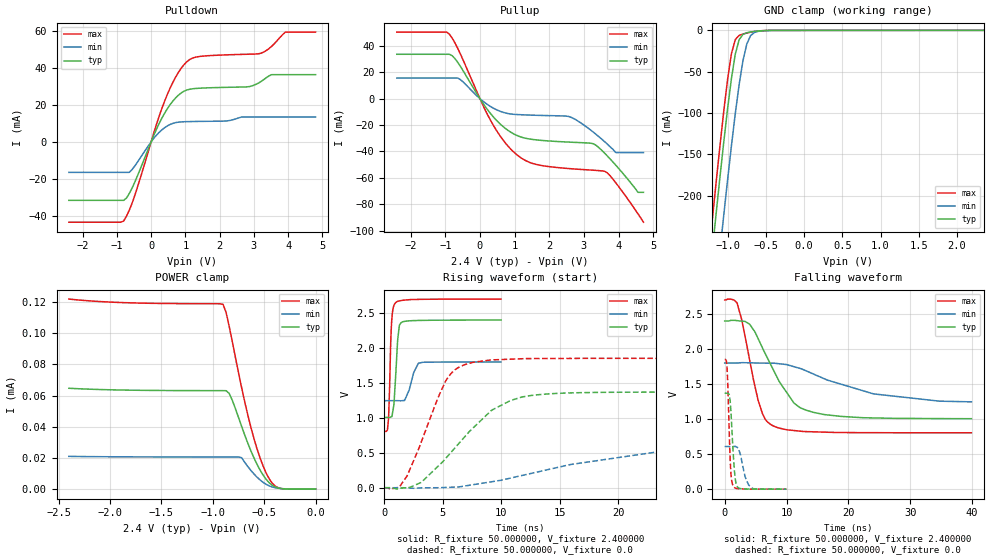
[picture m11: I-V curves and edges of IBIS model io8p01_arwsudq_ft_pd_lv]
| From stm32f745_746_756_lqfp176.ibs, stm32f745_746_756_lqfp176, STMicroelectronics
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|   Model io8p01_arwsudq_ft_pd_lv
[Model]  io8p01_arwsudq_ft_pd_lv
Model_type I/O
Polarity   Non-Inverting
Enable   Active-Low
Vinl =   0.720000V
Vinh =   1.680000V
Vmeas =  1.200000V
Cref =   50.000000pF
Rref =   100.000000M
Vref =   0.0V
C_comp   2.818400pF   2.774300pF   2.917100pF
[Temperature Range]   25.000000   0.125000k   -40.000000
[Pullup Reference]   2.400000V   1.800000V   2.700000V
[Pulldown Reference]   0.0V   0.0V   0.0V
[POWER Clamp Reference]   2.400000V   1.800000V   2.700000V
[GND Clamp Reference]   0.0V   0.0V   0.0V
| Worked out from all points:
|   slope of the pulldown table from 0 to 0.36 V, typ, clamps not added: 25 ohm
|   slope of the pullup table from 0 to 0.36 V, typ, clamps not added: 27.7 ohm
|   GND clamp passes 1 mA (typ) near -0.62 V on its own axis
|   rising waveform, R_fixture 50.000000, V_fixture 2.400000: 20-80 % time 290ps typ, 616ps min, 206ps max; typ from 1 V to 2.4 V
|   rising waveform, R_fixture 50.000000, V_fixture 0.0: 20-80 % time 4.7ns typ, 11.9ns min, 2.65ns max; typ from 0 V to 1.37 V
|   falling waveform, R_fixture 50.000000, V_fixture 2.400000: 20-80 % time 5.21ns typ, 11.2ns min, 2.74ns max; typ from 2.4 V to 1 V
|   falling waveform, R_fixture 50.000000, V_fixture 0.0: 20-80 % time 542ps typ, 1ns min, 409ps max; typ from 1.37 V to 0 V
[Pulldown]
|Voltage   I(typ)   I(min)   I(max)
-2.4V     -31.67mA   -16.51mA   -43.52mA
-800mV    -31.67mA   -16.51mA   -42.86mA
-480mV    -21.98mA   -13.17mA   -29.21mA
80mV      3.63mA     1.966mA    5.012mA
480mV     18.15mA    8.738mA    26.02mA
800mV     25.38mA    10.72mA    37.77mA
1.12V     28.53mA    11.02mA    44.6mA
2.8V      29.84mA    13.49mA    47.53mA
3.2V      32.65mA    13.49mA    48.03mA
3.52V     36.46mA    13.49mA    51.84mA
3.92V     36.46mA    13.49mA    59.54mA
4.8V      36.46mA    13.49mA    59.54mA
[Pullup]
|Voltage   I(typ)   I(min)   I(max)
-2.4V     33.58mA    15.57mA    50.37mA
-960mV    33.58mA    15.57mA    50.37mA
-560mV    24.28mA    14.31mA    33.53mA
320mV     -11.75mA   -6.207mA   -17.08mA
960mV     -26.47mA   -11.82mA   -40.02mA
1.52V     -30.88mA   -12.51mA   -49.05mA
2.56V     -32.88mA   -13.49mA   -52.9mA
3.28V     -34.2mA    -25.52mA   -54.18mA
3.6V      -41.32mA   -32.62mA   -54.99mA
3.92V     -50.34mA   -40.8mA    -63.66mA
4.56V     -70.9mA    -40.8mA    -87.12mA
4.72V     -70.9mA    -40.8mA    -93.5mA
[GND_clamp]
|Voltage   I(typ)   I(min)   I(max)
-2.4V     -1.425A    -1.508A    -1.394A
-1.25V    -311.8mA   -402mA     -274.5mA
-1.2V     -266mA     -356.2mA   -228.4mA
-1.15V    -220.9mA   -310.9mA   -183.1mA
-1.1V     -176.9mA   -266.3mA   -139mA
-1.05V    -134.3mA   -222.6mA   -97.01mA
-950mV    -57.82mA   -139.1mA   -27.87mA
-900mV    -28.73mA   -100.5mA   -11.05mA
-850mV    -11.3mA    -65.69mA   -6.068mA
-750mV    -2.863mA   -16.61mA   -3.194mA
-600mV    -761.3uA   -1.176mA   -752.1uA
2.35V     58.09uA    37.92uA    67.25uA
[POWER_clamp]
|Voltage   I(typ)   I(min)   I(max)
-2.4V     64.71uA    21.03uA    121.9uA
-1.86V    63.55uA    20.74uA    119.6uA
-900mV    63.18uA    20.63uA    118.5uA
-870mV    63.14uA    20.63uA    113.2uA
-840mV    61.36uA    20.62uA    104.3uA
-720mV    40.37uA    20.18uA    65.28uA
-630mV    24.69uA    12.08uA    39.85uA
-540mV    12.26uA    5.907uA    20uA
-480mV    6.236uA    3.061uA    10.23uA
-420mV    2.4uA      1.365uA    3.726uA
-360mV    667.9nA    564nA      839.6nA
0V        0A         0A         0A
[Ramp]
| variable   typ   min   max
dV/dt_r  0.82152/4.69968n   0.36482/11.92119n   1.11053/2.65221n
dV/dt_f  0.83664/5.21391n   0.32232/12.23448n   1.13683/2.73608n
R_load = 50.000000
[Rising Waveform]
R_fixture= 50.000000
V_fixture= 2.400000
V_fixture_min= 1.800000
V_fixture_max= 2.700000
|time   V(typ)   V(min)   V(max)
0s        1.005V     1.245V     804.3mV
260.3ps   1.005V     1.245V     830mV
340.3ps   1.005V     1.245V     973.3mV
600.6ps   1.015V     1.246V     2.332V
800.8ps   1.177V     1.246V     2.601V
920.9ps   1.489V     1.246V     2.641V
1.141ns   2.127V     1.245V     2.666V
1.481ns   2.367V     1.245V     2.679V
2.923ns   2.393V     1.782V     2.694V
9.97ns    2.399V     1.799V     2.699V
[Rising Waveform]
R_fixture= 50.000000
V_fixture= 0.0
V_fixture_min= 0.0
V_fixture_max= 0.0
|time   V(typ)   V(min)   V(max)
0s        179.6uV    73.8uV     513.7uV
1.281ns   -10.87mV   167.6uV    16.45mV
1.922ns   840.6uV    -2.445mV   164.6mV
3.123ns   74.88mV    -2.309mV   641.7mV
5.205ns   412.7mV    3.848mV    1.515V
6.887ns   731.9mV    25.03mV    1.762V
9.209ns   1.112V     86.55mV    1.829V
12.57ns   1.32V      205.6mV    1.847V
24.5ns    1.368V     540.7mV    1.851V
39.88ns   1.369V     608.4mV    1.851V
[Falling Waveform]
R_fixture= 50.000000
V_fixture= 2.400000
V_fixture_min= 1.800000
V_fixture_max= 2.700000
|time   V(typ)   V(min)   V(max)
0s        2.399V     1.799V     2.699V
2.002ns   2.404V     1.8V       2.657V
4.004ns   2.355V     1.803V     1.856V
5.445ns   2.14V      1.799V     1.256V
6.486ns   1.946V     1.798V     1.007V
7.688ns   1.734V     1.797V     909.6mV
11.21ns   1.227V     1.747V     836.4mV
14.25ns   1.098V     1.646V     818.4mV
24.02ns   1.016V     1.36V      805.8mV
39.88ns   1.005V     1.245V     804.3mV
[Falling Waveform]
R_fixture= 50.000000
V_fixture= 0.0
V_fixture_min= 0.0
V_fixture_max= 0.0
|time   V(typ)   V(min)   V(max)
0s        1.369V     608.4mV    1.851V
380.4ps   1.369V     608.4mV    1.728V
880.9ps   1.262V     608.2mV    436mV
1.081ns   988.4mV    607.9mV    154.3mV
1.361ns   526.9mV    608.1mV    46.97mV
1.722ns   137.2mV    610.2mV    15.43mV
2.202ns   20.6mV     584.3mV    6.119mV
3.303ns   2.95mV     176.6mV    2.513mV
4.505ns   1.491mV    9.372mV    1.209mV
9.97ns    179.6uV    73.8uV     513.7uV
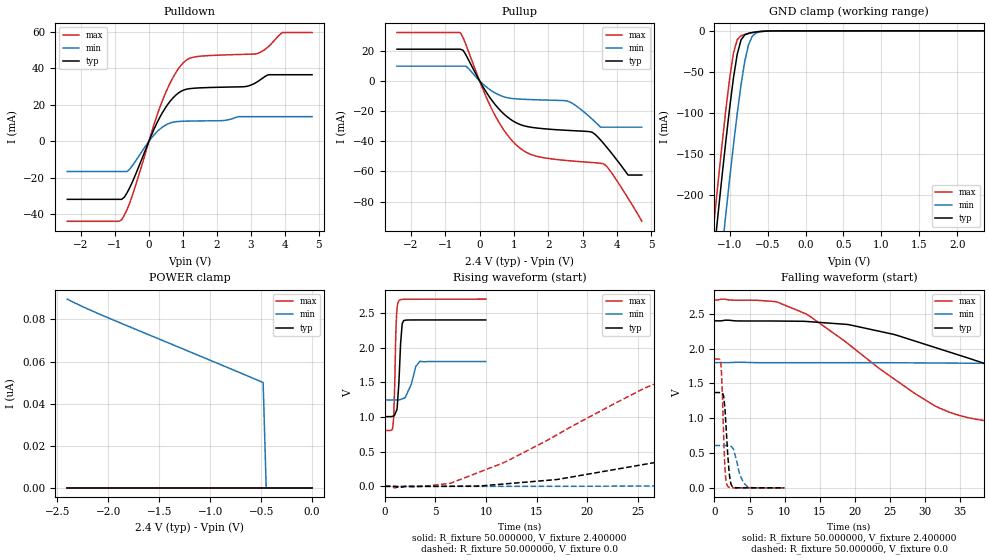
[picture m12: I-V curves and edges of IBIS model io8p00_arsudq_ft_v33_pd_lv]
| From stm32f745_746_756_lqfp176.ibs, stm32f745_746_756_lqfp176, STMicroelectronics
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|   Model io8p00_arsudq_ft_v33_pd_lv
[Model]  io8p00_arsudq_ft_v33_pd_lv
Model_type I/O
Polarity   Non-Inverting
Enable   Active-Low
Vinl =   0.720000V
Vinh =   1.680000V
Vmeas =  1.200000V
Cref =   50.000000pF
Rref =   100.000000M
Vref =   0.0V
C_comp   2.238700pF   2.180600pF   2.332300pF
[Temperature Range]   25.000000   0.125000k   -40.000000
[Pullup Reference]   2.400000V   1.800000V   2.700000V
[Pulldown Reference]   0.0V   0.0V   0.0V
[POWER Clamp Reference]   2.400000V   1.800000V   2.700000V
[GND Clamp Reference]   0.0V   0.0V   0.0V
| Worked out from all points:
|   slope of the pulldown table from 0 to 0.36 V, typ, clamps not added: 25 ohm
|   slope of the pullup table from 0 to 0.36 V, typ, clamps not added: 27.7 ohm
|   GND clamp passes 1 mA (typ) near -0.62 V on its own axis
|   rising waveform, R_fixture 50.000000, V_fixture 2.400000: 20-80 % time 302ps typ, 741ps min, 198ps max; typ from 1 V to 2.4 V
|   rising waveform, R_fixture 50.000000, V_fixture 0.0: 20-80 % time 30.9ns typ, 81.7ns min, 14.6ns max; typ from 0 V to 1.37 V
|   falling waveform, R_fixture 50.000000, V_fixture 2.400000: 20-80 % time 28.6ns typ, 81.4ns min, 15.7ns max; typ from 2.4 V to 1 V
|   falling waveform, R_fixture 50.000000, V_fixture 0.0: 20-80 % time 533ps typ, 1.03ns min, 385ps max; typ from 1.37 V to 0 V
[Pulldown]
|Voltage   I(typ)   I(min)   I(max)
-2.4V     -31.73mA   -16.51mA   -43.74mA
-800mV    -31.73mA   -16.51mA   -42.87mA
-480mV    -21.98mA   -13.17mA   -29.2mA
80mV      3.63mA     1.966mA    5.014mA
480mV     18.15mA    8.738mA    26.02mA
800mV     25.38mA    10.72mA    37.77mA
1.12V     28.53mA    11.02mA    44.6mA
2.8V      29.84mA    13.47mA    47.53mA
3.2V      32.64mA    13.47mA    48.04mA
3.52V     36.39mA    13.47mA    51.82mA
3.92V     36.39mA    13.47mA    59.43mA
4.8V      36.39mA    13.47mA    59.43mA
[Pullup]
|Voltage   I(typ)   I(min)   I(max)
-2.4V     20.89mA    9.659mA    31.9mA
-560mV    20.89mA    9.659mA    31.9mA
-400mV    17.28mA    9.659mA    24.07mA
320mV     -11.75mA   -6.207mA   -17.08mA
640mV     -20.52mA   -10.1mA    -30.35mA
960mV     -26.47mA   -11.82mA   -40.02mA
1.52V     -30.88mA   -12.51mA   -49.05mA
2.56V     -32.88mA   -13.48mA   -52.9mA
3.28V     -34.19mA   -25.51mA   -54.18mA
3.6V      -41.31mA   -30.75mA   -54.97mA
4.32V     -62.46mA   -30.75mA   -77.8mA
4.72V     -62.46mA   -30.75mA   -93.1mA
[GND_clamp]
|Voltage   I(typ)   I(min)   I(max)
-2.4V     -1.424A    -1.508A    -1.394A
-1.25V    -311.2mA   -401.9mA   -273.3mA
-1.2V     -265.4mA   -356.1mA   -227.2mA
-1.15V    -220.4mA   -310.8mA   -181.9mA
-1.1V     -176.3mA   -266.2mA   -137.9mA
-1.05V    -133.8mA   -222.5mA   -95.87mA
-950mV    -57.3mA    -138.9mA   -26.99mA
-900mV    -28.28mA   -100.4mA   -10.6mA
-850mV    -11.02mA   -65.54mA   -5.972mA
-750mV    -2.846mA   -16.51mA   -3.192mA
-600mV    -761.3uA   -1.173mA   -751.9uA
2.35V     58.09uA    37.92uA    67.25uA
[POWER_clamp]
|Voltage   I(typ)   I(min)   I(max)
-2.4V     0A         89.62nA    0A
-2.04V    0A         81.57nA    0A
-480mV    0A         50.01nA    0A
-450mV    0A         0A         0A
0V        0A         0A         0A
[Ramp]
| variable   typ   min   max
dV/dt_r  0.82170/30.92727n   0.36271/83.81137n   1.11042/14.59282n
dV/dt_f  0.83646/28.58942n   0.32706/81.77596n   1.13678/15.72077n
R_load = 50.000000
[Rising Waveform]
R_fixture= 50.000000
V_fixture= 2.400000
V_fixture_min= 1.800000
V_fixture_max= 2.700000
|time   V(typ)   V(min)   V(max)
0s        1.005V     1.245V     804.1mV
780.8ps   1.011V     1.245V     846.4mV
880.9ps   1.015V     1.245V     996.6mV
1.161ns   1.094V     1.245V     2.467V
1.401ns   1.515V     1.245V     2.678V
1.562ns   2.057V     1.253V     2.693V
1.722ns   2.344V     1.261V     2.695V
1.862ns   2.389V     1.268V     2.696V
3.463ns   2.399V     1.803V     2.698V
9.97ns    2.399V     1.799V     2.699V
[Rising Waveform]
R_fixture= 50.000000
V_fixture= 0.0
V_fixture_min= 0.0
V_fixture_max= 0.0
|time   V(typ)   V(min)   V(max)
0s        7.691nV    244.8nV    27.4nV
6.507ns   922.5uV    -66.36uV   44.91mV
17.02ns   98.58mV    89.21uV    743.8mV
28.03ns   377.6mV    6.718mV    1.545V
34.53ns   558.1mV    13.45mV    1.714V
42.54ns   789.1mV    40.96mV    1.79V
59.56ns   1.171V     99.42mV    1.838V
84.08ns   1.327V     215.4mV    1.848V
153.2ns   1.367V     510.1mV    1.851V
249.2ns   1.369V     608.5mV    1.851V
[Falling Waveform]
R_fixture= 50.000000
V_fixture= 2.400000
V_fixture_min= 1.800000
V_fixture_max= 2.700000
|time   V(typ)   V(min)   V(max)
0s        2.399V     1.799V     2.699V
9.009ns   2.396V     1.798V     2.667V
19.02ns   2.347V     1.798V     2.073V
31.53ns   2.015V     1.794V     1.173V
37.04ns   1.837V     1.79V      991.3mV
46.55ns   1.527V     1.764V     891.8mV
61.06ns   1.226V     1.712V     844mV
87.09ns   1.073V     1.567V     816.1mV
157.2ns   1.013V     1.322V     804.9mV
249.2ns   1.005V     1.245V     804.1mV
[Falling Waveform]
R_fixture= 50.000000
V_fixture= 0.0
V_fixture_min= 0.0
V_fixture_max= 0.0
|time   V(typ)   V(min)   V(max)
0s        1.369V     608.5mV    1.851V
900.9ps   1.37V      608.3mV    1.79V
1.101ns   1.366V     608.2mV    1.399V
1.481ns   1.146V     607.9mV    309.3mV
1.862ns   521.9mV    608.8mV    27.4mV
2.242ns   105.6mV    605.9mV    3.626mV
2.643ns   12.34mV    565.5mV    634.2uV
3.584ns   477.1uV    200.2mV    42.73uV
4.805ns   23.47uV    8.21mV     24.44uV
9.97ns    7.691nV    244.8nV    27.4nV
